VERSION 5.7 ;
  NOWIREEXTENSIONATPIN ON ;
  DIVIDERCHAR "/" ;
  BUSBITCHARS "[]" ;
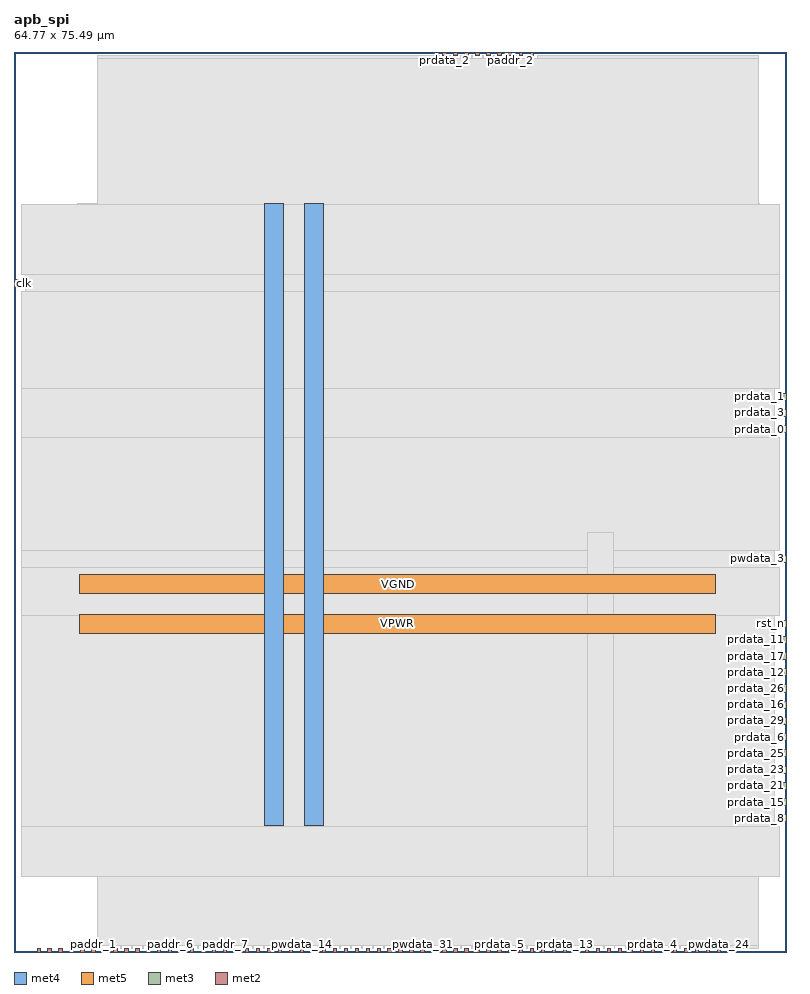
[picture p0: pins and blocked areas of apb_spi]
MACRO apb_spi
  CLASS BLOCK ;
  FOREIGN apb_spi ;
  ORIGIN 0.000 0.000 ;
  SIZE 64.770 BY 75.490 ;
  PIN VGND
    DIRECTION INOUT ;
    USE GROUND ;
    PORT
      LAYER met4 ;
        RECT 24.340 10.640 25.940 62.800 ;
    END
    PORT
      LAYER met5 ;
        RECT 5.520 30.030 58.880 31.630 ;
    END
  END VGND
  PIN VPWR
    DIRECTION INOUT ;
    USE POWER ;
    PORT
      LAYER met4 ;
        RECT 21.040 10.640 22.640 62.800 ;
    END
    PORT
      LAYER met5 ;
        RECT 5.520 26.730 58.880 28.330 ;
    END
  END VPWR
  PIN clk
    DIRECTION INPUT ;
    USE SIGNAL ;
    ANTENNAGATEAREA 1.286700 ;
    ANTENNADIFFAREA 0.434700 ;
    PORT
      LAYER met3 ;
        RECT 0.000 55.800 0.600 56.400 ;
    END
  END clk
  PIN paddr_0
    DIRECTION INPUT ;
    USE SIGNAL ;
    PORT
      LAYER met2 ;
        RECT 2.850 0.000 3.130 0.280 ;
    END
  END paddr_0
  PIN paddr_1
    DIRECTION INPUT ;
    USE SIGNAL ;
    PORT
      LAYER met2 ;
        RECT 6.530 0.000 6.810 0.280 ;
    END
  END paddr_1
  PIN paddr_10
    DIRECTION INPUT ;
    USE SIGNAL ;
    PORT
      LAYER met2 ;
        RECT 10.210 0.000 10.490 0.280 ;
    END
  END paddr_10
  PIN paddr_11
    DIRECTION INPUT ;
    USE SIGNAL ;
    PORT
      LAYER met2 ;
        RECT 8.370 0.000 8.650 0.280 ;
    END
  END paddr_11
  PIN paddr_2
    DIRECTION INPUT ;
    USE SIGNAL ;
    ANTENNAGATEAREA 0.647700 ;
    ANTENNADIFFAREA 0.434700 ;
    PORT
      LAYER met2 ;
        RECT 41.490 75.210 41.770 75.490 ;
    END
  END paddr_2
  PIN paddr_3
    DIRECTION INPUT ;
    USE SIGNAL ;
    ANTENNAGATEAREA 0.647700 ;
    ANTENNADIFFAREA 0.434700 ;
    PORT
      LAYER met2 ;
        RECT 40.570 75.210 40.850 75.490 ;
    END
  END paddr_3
  PIN paddr_4
    DIRECTION INPUT ;
    USE SIGNAL ;
    ANTENNAGATEAREA 0.647700 ;
    ANTENNADIFFAREA 0.434700 ;
    PORT
      LAYER met2 ;
        RECT 39.650 75.210 39.930 75.490 ;
    END
  END paddr_4
  PIN paddr_5
    DIRECTION INPUT ;
    USE SIGNAL ;
    PORT
      LAYER met2 ;
        RECT 5.610 0.000 5.890 0.280 ;
    END
  END paddr_5
  PIN paddr_6
    DIRECTION INPUT ;
    USE SIGNAL ;
    PORT
      LAYER met2 ;
        RECT 12.970 0.000 13.250 0.280 ;
    END
  END paddr_6
  PIN paddr_7
    DIRECTION INPUT ;
    USE SIGNAL ;
    PORT
      LAYER met2 ;
        RECT 17.570 0.000 17.850 0.280 ;
    END
  END paddr_7
  PIN paddr_8
    DIRECTION INPUT ;
    USE SIGNAL ;
    PORT
      LAYER met2 ;
        RECT 12.050 0.000 12.330 0.280 ;
    END
  END paddr_8
  PIN paddr_9
    DIRECTION INPUT ;
    USE SIGNAL ;
    PORT
      LAYER met2 ;
        RECT 9.290 0.000 9.570 0.280 ;
    END
  END paddr_9
  PIN penable
    DIRECTION INPUT ;
    USE SIGNAL ;
    ANTENNAGATEAREA 0.647700 ;
    ANTENNADIFFAREA 0.434700 ;
    PORT
      LAYER met2 ;
        RECT 38.730 75.210 39.010 75.490 ;
    END
  END penable
  PIN prdata_0
    DIRECTION OUTPUT ;
    USE SIGNAL ;
    ANTENNAGATEAREA 0.434700 ;
    ANTENNADIFFAREA 1.137600 ;
    PORT
      LAYER met3 ;
        RECT 64.170 43.560 64.770 44.160 ;
    END
  END prdata_0
  PIN prdata_1
    DIRECTION OUTPUT ;
    USE SIGNAL ;
    ANTENNAGATEAREA 0.434700 ;
    ANTENNADIFFAREA 1.137600 ;
    PORT
      LAYER met3 ;
        RECT 64.170 46.280 64.770 46.880 ;
    END
  END prdata_1
  PIN prdata_10
    DIRECTION OUTPUT ;
    USE SIGNAL ;
    ANTENNAGATEAREA 0.434700 ;
    ANTENNADIFFAREA 0.775300 ;
    PORT
      LAYER met2 ;
        RECT 35.050 0.000 35.330 0.280 ;
    END
  END prdata_10
  PIN prdata_11
    DIRECTION OUTPUT ;
    USE SIGNAL ;
    ANTENNAGATEAREA 0.434700 ;
    ANTENNADIFFAREA 0.775300 ;
    PORT
      LAYER met3 ;
        RECT 64.170 25.880 64.770 26.480 ;
    END
  END prdata_11
  PIN prdata_12
    DIRECTION OUTPUT ;
    USE SIGNAL ;
    ANTENNAGATEAREA 0.434700 ;
    ANTENNADIFFAREA 0.775300 ;
    PORT
      LAYER met3 ;
        RECT 64.170 23.160 64.770 23.760 ;
    END
  END prdata_12
  PIN prdata_13
    DIRECTION OUTPUT ;
    USE SIGNAL ;
    ANTENNAGATEAREA 0.434700 ;
    ANTENNADIFFAREA 0.775300 ;
    PORT
      LAYER met2 ;
        RECT 46.090 0.000 46.370 0.280 ;
    END
  END prdata_13
  PIN prdata_14
    DIRECTION OUTPUT ;
    USE SIGNAL ;
    ANTENNAGATEAREA 0.434700 ;
    ANTENNADIFFAREA 0.775300 ;
    PORT
      LAYER met2 ;
        RECT 52.530 0.000 52.810 0.280 ;
    END
  END prdata_14
  PIN prdata_15
    DIRECTION OUTPUT ;
    USE SIGNAL ;
    ANTENNAGATEAREA 0.434700 ;
    ANTENNADIFFAREA 0.775300 ;
    PORT
      LAYER met3 ;
        RECT 64.170 12.280 64.770 12.880 ;
    END
  END prdata_15
  PIN prdata_16
    DIRECTION OUTPUT ;
    USE SIGNAL ;
    ANTENNAGATEAREA 0.434700 ;
    ANTENNADIFFAREA 0.775300 ;
    PORT
      LAYER met3 ;
        RECT 64.170 20.440 64.770 21.040 ;
    END
  END prdata_16
  PIN prdata_17
    DIRECTION OUTPUT ;
    USE SIGNAL ;
    ANTENNAGATEAREA 0.434700 ;
    ANTENNADIFFAREA 0.775300 ;
    PORT
      LAYER met3 ;
        RECT 64.170 24.520 64.770 25.120 ;
    END
  END prdata_17
  PIN prdata_18
    DIRECTION OUTPUT ;
    USE SIGNAL ;
    ANTENNAGATEAREA 0.434700 ;
    ANTENNADIFFAREA 0.775300 ;
    PORT
      LAYER met2 ;
        RECT 51.610 0.000 51.890 0.280 ;
    END
  END prdata_18
  PIN prdata_19
    DIRECTION OUTPUT ;
    USE SIGNAL ;
    ANTENNAGATEAREA 0.434700 ;
    ANTENNADIFFAREA 0.775300 ;
    PORT
      LAYER met2 ;
        RECT 44.250 0.000 44.530 0.280 ;
    END
  END prdata_19
  PIN prdata_2
    DIRECTION OUTPUT ;
    USE SIGNAL ;
    ANTENNAGATEAREA 0.434700 ;
    ANTENNADIFFAREA 1.137600 ;
    PORT
      LAYER met2 ;
        RECT 35.970 75.210 36.250 75.490 ;
    END
  END prdata_2
  PIN prdata_20
    DIRECTION OUTPUT ;
    USE SIGNAL ;
    ANTENNAGATEAREA 0.434700 ;
    ANTENNADIFFAREA 0.775300 ;
    PORT
      LAYER met2 ;
        RECT 36.890 0.000 37.170 0.280 ;
    END
  END prdata_20
  PIN prdata_21
    DIRECTION OUTPUT ;
    USE SIGNAL ;
    ANTENNAGATEAREA 0.434700 ;
    ANTENNADIFFAREA 0.775300 ;
    PORT
      LAYER met3 ;
        RECT 64.170 13.640 64.770 14.240 ;
    END
  END prdata_21
  PIN prdata_22
    DIRECTION OUTPUT ;
    USE SIGNAL ;
    ANTENNAGATEAREA 0.434700 ;
    ANTENNADIFFAREA 0.775300 ;
    PORT
      LAYER met2 ;
        RECT 48.850 0.000 49.130 0.280 ;
    END
  END prdata_22
  PIN prdata_23
    DIRECTION OUTPUT ;
    USE SIGNAL ;
    ANTENNAGATEAREA 0.434700 ;
    ANTENNADIFFAREA 0.775300 ;
    PORT
      LAYER met3 ;
        RECT 64.170 15.000 64.770 15.600 ;
    END
  END prdata_23
  PIN prdata_24
    DIRECTION OUTPUT ;
    USE SIGNAL ;
    ANTENNAGATEAREA 0.434700 ;
    ANTENNADIFFAREA 0.775300 ;
    PORT
      LAYER met2 ;
        RECT 47.010 0.000 47.290 0.280 ;
    END
  END prdata_24
  PIN prdata_25
    DIRECTION OUTPUT ;
    USE SIGNAL ;
    ANTENNAGATEAREA 0.434700 ;
    ANTENNADIFFAREA 0.775300 ;
    PORT
      LAYER met3 ;
        RECT 64.170 16.360 64.770 16.960 ;
    END
  END prdata_25
  PIN prdata_26
    DIRECTION OUTPUT ;
    USE SIGNAL ;
    ANTENNAGATEAREA 0.434700 ;
    ANTENNADIFFAREA 0.775300 ;
    PORT
      LAYER met3 ;
        RECT 64.170 21.800 64.770 22.400 ;
    END
  END prdata_26
  PIN prdata_27
    DIRECTION OUTPUT ;
    USE SIGNAL ;
    ANTENNAGATEAREA 0.434700 ;
    ANTENNADIFFAREA 0.775300 ;
    PORT
      LAYER met2 ;
        RECT 37.810 0.000 38.090 0.280 ;
    END
  END prdata_27
  PIN prdata_28
    DIRECTION OUTPUT ;
    USE SIGNAL ;
    ANTENNAGATEAREA 0.434700 ;
    ANTENNADIFFAREA 0.775300 ;
    PORT
      LAYER met2 ;
        RECT 50.690 0.000 50.970 0.280 ;
    END
  END prdata_28
  PIN prdata_29
    DIRECTION OUTPUT ;
    USE SIGNAL ;
    ANTENNAGATEAREA 0.434700 ;
    ANTENNADIFFAREA 0.775300 ;
    PORT
      LAYER met3 ;
        RECT 64.170 19.080 64.770 19.680 ;
    END
  END prdata_29
  PIN prdata_3
    DIRECTION OUTPUT ;
    USE SIGNAL ;
    ANTENNAGATEAREA 0.434700 ;
    ANTENNADIFFAREA 1.137600 ;
    PORT
      LAYER met3 ;
        RECT 64.170 44.920 64.770 45.520 ;
    END
  END prdata_3
  PIN prdata_30
    DIRECTION OUTPUT ;
    USE SIGNAL ;
    ANTENNAGATEAREA 0.434700 ;
    ANTENNADIFFAREA 0.775300 ;
    PORT
      LAYER met2 ;
        RECT 49.770 0.000 50.050 0.280 ;
    END
  END prdata_30
  PIN prdata_31
    DIRECTION OUTPUT ;
    USE SIGNAL ;
    ANTENNAGATEAREA 0.434700 ;
    ANTENNADIFFAREA 0.775300 ;
    PORT
      LAYER met2 ;
        RECT 43.330 0.000 43.610 0.280 ;
    END
  END prdata_31
  PIN prdata_4
    DIRECTION OUTPUT ;
    USE SIGNAL ;
    ANTENNAGATEAREA 0.434700 ;
    ANTENNADIFFAREA 0.434700 ;
    PORT
      LAYER met2 ;
        RECT 53.450 0.000 53.730 0.280 ;
    END
  END prdata_4
  PIN prdata_5
    DIRECTION OUTPUT ;
    USE SIGNAL ;
    ANTENNAGATEAREA 0.434700 ;
    ANTENNADIFFAREA 0.775300 ;
    PORT
      LAYER met2 ;
        RECT 40.570 0.000 40.850 0.280 ;
    END
  END prdata_5
  PIN prdata_6
    DIRECTION OUTPUT ;
    USE SIGNAL ;
    ANTENNAGATEAREA 0.434700 ;
    ANTENNADIFFAREA 0.775300 ;
    PORT
      LAYER met3 ;
        RECT 64.170 17.720 64.770 18.320 ;
    END
  END prdata_6
  PIN prdata_7
    DIRECTION OUTPUT ;
    USE SIGNAL ;
    ANTENNAGATEAREA 0.434700 ;
    ANTENNADIFFAREA 0.775300 ;
    PORT
      LAYER met2 ;
        RECT 39.650 0.000 39.930 0.280 ;
    END
  END prdata_7
  PIN prdata_8
    DIRECTION OUTPUT ;
    USE SIGNAL ;
    ANTENNAGATEAREA 0.434700 ;
    ANTENNADIFFAREA 0.775300 ;
    PORT
      LAYER met3 ;
        RECT 64.170 10.920 64.770 11.520 ;
    END
  END prdata_8
  PIN prdata_9
    DIRECTION OUTPUT ;
    USE SIGNAL ;
    ANTENNAGATEAREA 0.434700 ;
    ANTENNADIFFAREA 0.775300 ;
    PORT
      LAYER met2 ;
        RECT 42.410 0.000 42.690 0.280 ;
    END
  END prdata_9
  PIN pready
    DIRECTION OUTPUT ;
    USE SIGNAL ;
    PORT
      LAYER met2 ;
        RECT 13.890 0.000 14.170 0.280 ;
    END
  END pready
  PIN psel
    DIRECTION INPUT ;
    USE SIGNAL ;
    ANTENNAGATEAREA 0.647700 ;
    ANTENNADIFFAREA 0.434700 ;
    PORT
      LAYER met2 ;
        RECT 36.890 75.210 37.170 75.490 ;
    END
  END psel
  PIN pslverr
    DIRECTION OUTPUT ;
    USE SIGNAL ;
    ANTENNAGATEAREA 0.434700 ;
    ANTENNADIFFAREA 0.775300 ;
    PORT
      LAYER met2 ;
        RECT 41.490 0.000 41.770 0.280 ;
    END
  END pslverr
  PIN pwdata_0
    DIRECTION INPUT ;
    USE SIGNAL ;
    ANTENNAGATEAREA 0.647700 ;
    ANTENNADIFFAREA 0.434700 ;
    PORT
      LAYER met2 ;
        RECT 30.450 0.000 30.730 0.280 ;
    END
  END pwdata_0
  PIN pwdata_1
    DIRECTION INPUT ;
    USE SIGNAL ;
    ANTENNAGATEAREA 0.647700 ;
    ANTENNADIFFAREA 0.434700 ;
    PORT
      LAYER met2 ;
        RECT 43.330 75.210 43.610 75.490 ;
    END
  END pwdata_1
  PIN pwdata_10
    DIRECTION INPUT ;
    USE SIGNAL ;
    PORT
      LAYER met2 ;
        RECT 14.810 0.000 15.090 0.280 ;
    END
  END pwdata_10
  PIN pwdata_11
    DIRECTION INPUT ;
    USE SIGNAL ;
    PORT
      LAYER met2 ;
        RECT 15.730 0.000 16.010 0.280 ;
    END
  END pwdata_11
  PIN pwdata_12
    DIRECTION INPUT ;
    USE SIGNAL ;
    PORT
      LAYER met2 ;
        RECT 19.410 0.000 19.690 0.280 ;
    END
  END pwdata_12
  PIN pwdata_13
    DIRECTION INPUT ;
    USE SIGNAL ;
    PORT
      LAYER met2 ;
        RECT 4.690 0.000 4.970 0.280 ;
    END
  END pwdata_13
  PIN pwdata_14
    DIRECTION INPUT ;
    USE SIGNAL ;
    PORT
      LAYER met2 ;
        RECT 24.010 0.000 24.290 0.280 ;
    END
  END pwdata_14
  PIN pwdata_15
    DIRECTION INPUT ;
    USE SIGNAL ;
    PORT
      LAYER met2 ;
        RECT 7.450 0.000 7.730 0.280 ;
    END
  END pwdata_15
  PIN pwdata_16
    DIRECTION INPUT ;
    USE SIGNAL ;
    PORT
      LAYER met2 ;
        RECT 33.210 0.000 33.490 0.280 ;
    END
  END pwdata_16
  PIN pwdata_17
    DIRECTION INPUT ;
    USE SIGNAL ;
    PORT
      LAYER met2 ;
        RECT 23.090 0.000 23.370 0.280 ;
    END
  END pwdata_17
  PIN pwdata_18
    DIRECTION INPUT ;
    USE SIGNAL ;
    PORT
      LAYER met2 ;
        RECT 18.490 0.000 18.770 0.280 ;
    END
  END pwdata_18
  PIN pwdata_19
    DIRECTION INPUT ;
    USE SIGNAL ;
    PORT
      LAYER met2 ;
        RECT 21.250 0.000 21.530 0.280 ;
    END
  END pwdata_19
  PIN pwdata_2
    DIRECTION INPUT ;
    USE SIGNAL ;
    ANTENNAGATEAREA 0.647700 ;
    ANTENNADIFFAREA 0.434700 ;
    PORT
      LAYER met2 ;
        RECT 42.410 75.210 42.690 75.490 ;
    END
  END pwdata_2
  PIN pwdata_20
    DIRECTION INPUT ;
    USE SIGNAL ;
    PORT
      LAYER met2 ;
        RECT 20.330 0.000 20.610 0.280 ;
    END
  END pwdata_20
  PIN pwdata_21
    DIRECTION INPUT ;
    USE SIGNAL ;
    PORT
      LAYER met2 ;
        RECT 26.770 0.000 27.050 0.280 ;
    END
  END pwdata_21
  PIN pwdata_22
    DIRECTION INPUT ;
    USE SIGNAL ;
    PORT
      LAYER met2 ;
        RECT 22.170 0.000 22.450 0.280 ;
    END
  END pwdata_22
  PIN pwdata_23
    DIRECTION INPUT ;
    USE SIGNAL ;
    PORT
      LAYER met2 ;
        RECT 24.930 0.000 25.210 0.280 ;
    END
  END pwdata_23
  PIN pwdata_24
    DIRECTION INPUT ;
    USE SIGNAL ;
    PORT
      LAYER met2 ;
        RECT 58.970 0.000 59.250 0.280 ;
    END
  END pwdata_24
  PIN pwdata_25
    DIRECTION INPUT ;
    USE SIGNAL ;
    PORT
      LAYER met2 ;
        RECT 27.690 0.000 27.970 0.280 ;
    END
  END pwdata_25
  PIN pwdata_26
    DIRECTION INPUT ;
    USE SIGNAL ;
    PORT
      LAYER met2 ;
        RECT 1.930 0.000 2.210 0.280 ;
    END
  END pwdata_26
  PIN pwdata_27
    DIRECTION INPUT ;
    USE SIGNAL ;
    PORT
      LAYER met2 ;
        RECT 32.290 0.000 32.570 0.280 ;
    END
  END pwdata_27
  PIN pwdata_28
    DIRECTION INPUT ;
    USE SIGNAL ;
    PORT
      LAYER met2 ;
        RECT 31.370 0.000 31.650 0.280 ;
    END
  END pwdata_28
  PIN pwdata_29
    DIRECTION INPUT ;
    USE SIGNAL ;
    PORT
      LAYER met2 ;
        RECT 55.290 0.000 55.570 0.280 ;
    END
  END pwdata_29
  PIN pwdata_3
    DIRECTION INPUT ;
    USE SIGNAL ;
    ANTENNAGATEAREA 0.647700 ;
    ANTENNADIFFAREA 0.434700 ;
    PORT
      LAYER met3 ;
        RECT 64.170 32.680 64.770 33.280 ;
    END
  END pwdata_3
  PIN pwdata_30
    DIRECTION INPUT ;
    USE SIGNAL ;
    PORT
      LAYER met2 ;
        RECT 29.530 0.000 29.810 0.280 ;
    END
  END pwdata_30
  PIN pwdata_31
    DIRECTION INPUT ;
    USE SIGNAL ;
    PORT
      LAYER met2 ;
        RECT 34.130 0.000 34.410 0.280 ;
    END
  END pwdata_31
  PIN pwdata_4
    DIRECTION INPUT ;
    USE SIGNAL ;
    ANTENNAGATEAREA 0.647700 ;
    ANTENNADIFFAREA 0.434700 ;
    PORT
      LAYER met2 ;
        RECT 38.730 0.000 39.010 0.280 ;
    END
  END pwdata_4
  PIN pwdata_5
    DIRECTION INPUT ;
    USE SIGNAL ;
    ANTENNAGATEAREA 0.647700 ;
    ANTENNADIFFAREA 0.434700 ;
    PORT
      LAYER met2 ;
        RECT 35.970 0.000 36.250 0.280 ;
    END
  END pwdata_5
  PIN pwdata_6
    DIRECTION INPUT ;
    USE SIGNAL ;
    ANTENNAGATEAREA 0.647700 ;
    ANTENNADIFFAREA 0.434700 ;
    PORT
      LAYER met2 ;
        RECT 28.610 0.000 28.890 0.280 ;
    END
  END pwdata_6
  PIN pwdata_7
    DIRECTION INPUT ;
    USE SIGNAL ;
    ANTENNAGATEAREA 0.647700 ;
    ANTENNADIFFAREA 0.434700 ;
    PORT
      LAYER met2 ;
        RECT 25.850 0.000 26.130 0.280 ;
    END
  END pwdata_7
  PIN pwdata_8
    DIRECTION INPUT ;
    USE SIGNAL ;
    PORT
      LAYER met2 ;
        RECT 58.050 0.000 58.330 0.280 ;
    END
  END pwdata_8
  PIN pwdata_9
    DIRECTION INPUT ;
    USE SIGNAL ;
    PORT
      LAYER met2 ;
        RECT 56.210 0.000 56.490 0.280 ;
    END
  END pwdata_9
  PIN pwrite
    DIRECTION INPUT ;
    USE SIGNAL ;
    ANTENNAGATEAREA 0.647700 ;
    ANTENNADIFFAREA 0.434700 ;
    PORT
      LAYER met2 ;
        RECT 37.810 75.210 38.090 75.490 ;
    END
  END pwrite
  PIN rst_n
    DIRECTION INPUT ;
    USE SIGNAL ;
    ANTENNAGATEAREA 0.647700 ;
    ANTENNADIFFAREA 0.434700 ;
    PORT
      LAYER met3 ;
        RECT 64.170 27.240 64.770 27.840 ;
    END
  END rst_n
  PIN spi_cs_n_0
    DIRECTION OUTPUT ;
    USE SIGNAL ;
    PORT
      LAYER met2 ;
        RECT 57.130 0.000 57.410 0.280 ;
    END
  END spi_cs_n_0
  PIN spi_cs_n_1
    DIRECTION OUTPUT ;
    USE SIGNAL ;
    PORT
      LAYER met2 ;
        RECT 3.770 0.000 4.050 0.280 ;
    END
  END spi_cs_n_1
  PIN spi_cs_n_2
    DIRECTION OUTPUT ;
    USE SIGNAL ;
    PORT
      LAYER met2 ;
        RECT 54.370 0.000 54.650 0.280 ;
    END
  END spi_cs_n_2
  PIN spi_cs_n_3
    DIRECTION OUTPUT ;
    USE SIGNAL ;
    PORT
      LAYER met2 ;
        RECT 16.650 0.000 16.930 0.280 ;
    END
  END spi_cs_n_3
  PIN spi_miso
    DIRECTION INPUT ;
    USE SIGNAL ;
    PORT
      LAYER met2 ;
        RECT 11.130 0.000 11.410 0.280 ;
    END
  END spi_miso
  PIN spi_mosi
    DIRECTION OUTPUT ;
    USE SIGNAL ;
    ANTENNAGATEAREA 0.434700 ;
    ANTENNADIFFAREA 0.775300 ;
    PORT
      LAYER met2 ;
        RECT 47.930 0.000 48.210 0.280 ;
    END
  END spi_mosi
  PIN spi_sclk
    DIRECTION OUTPUT ;
    USE SIGNAL ;
    ANTENNAGATEAREA 0.434700 ;
    ANTENNADIFFAREA 0.775300 ;
    PORT
      LAYER met2 ;
        RECT 45.170 0.000 45.450 0.280 ;
    END
  END spi_sclk
  OBS
      LAYER nwell ;
        RECT 5.330 10.795 59.070 62.750 ;
      LAYER li1 ;
        RECT 5.520 10.795 58.880 62.645 ;
      LAYER met1 ;
        RECT 5.520 6.500 62.490 62.800 ;
      LAYER met2 ;
        RECT 7.000 74.930 35.690 75.210 ;
        RECT 36.530 74.930 36.610 75.210 ;
        RECT 37.450 74.930 37.530 75.210 ;
        RECT 38.370 74.930 38.450 75.210 ;
        RECT 39.290 74.930 39.370 75.210 ;
        RECT 40.210 74.930 40.290 75.210 ;
        RECT 41.130 74.930 41.210 75.210 ;
        RECT 42.050 74.930 42.130 75.210 ;
        RECT 42.970 74.930 43.050 75.210 ;
        RECT 43.890 74.930 62.470 75.210 ;
        RECT 7.000 0.560 62.470 74.930 ;
        RECT 7.090 0.280 7.170 0.560 ;
        RECT 8.010 0.280 8.090 0.560 ;
        RECT 8.930 0.280 9.010 0.560 ;
        RECT 9.850 0.280 9.930 0.560 ;
        RECT 10.770 0.280 10.850 0.560 ;
        RECT 11.690 0.280 11.770 0.560 ;
        RECT 12.610 0.280 12.690 0.560 ;
        RECT 13.530 0.280 13.610 0.560 ;
        RECT 14.450 0.280 14.530 0.560 ;
        RECT 15.370 0.280 15.450 0.560 ;
        RECT 16.290 0.280 16.370 0.560 ;
        RECT 17.210 0.280 17.290 0.560 ;
        RECT 18.130 0.280 18.210 0.560 ;
        RECT 19.050 0.280 19.130 0.560 ;
        RECT 19.970 0.280 20.050 0.560 ;
        RECT 20.890 0.280 20.970 0.560 ;
        RECT 21.810 0.280 21.890 0.560 ;
        RECT 22.730 0.280 22.810 0.560 ;
        RECT 23.650 0.280 23.730 0.560 ;
        RECT 24.570 0.280 24.650 0.560 ;
        RECT 25.490 0.280 25.570 0.560 ;
        RECT 26.410 0.280 26.490 0.560 ;
        RECT 27.330 0.280 27.410 0.560 ;
        RECT 28.250 0.280 28.330 0.560 ;
        RECT 29.170 0.280 29.250 0.560 ;
        RECT 30.090 0.280 30.170 0.560 ;
        RECT 31.010 0.280 31.090 0.560 ;
        RECT 31.930 0.280 32.010 0.560 ;
        RECT 32.850 0.280 32.930 0.560 ;
        RECT 33.770 0.280 33.850 0.560 ;
        RECT 34.690 0.280 34.770 0.560 ;
        RECT 35.610 0.280 35.690 0.560 ;
        RECT 36.530 0.280 36.610 0.560 ;
        RECT 37.450 0.280 37.530 0.560 ;
        RECT 38.370 0.280 38.450 0.560 ;
        RECT 39.290 0.280 39.370 0.560 ;
        RECT 40.210 0.280 40.290 0.560 ;
        RECT 41.130 0.280 41.210 0.560 ;
        RECT 42.050 0.280 42.130 0.560 ;
        RECT 42.970 0.280 43.050 0.560 ;
        RECT 43.890 0.280 43.970 0.560 ;
        RECT 44.810 0.280 44.890 0.560 ;
        RECT 45.730 0.280 45.810 0.560 ;
        RECT 46.650 0.280 46.730 0.560 ;
        RECT 47.570 0.280 47.650 0.560 ;
        RECT 48.490 0.280 48.570 0.560 ;
        RECT 49.410 0.280 49.490 0.560 ;
        RECT 50.330 0.280 50.410 0.560 ;
        RECT 51.250 0.280 51.330 0.560 ;
        RECT 52.170 0.280 52.250 0.560 ;
        RECT 53.090 0.280 53.170 0.560 ;
        RECT 54.010 0.280 54.090 0.560 ;
        RECT 54.930 0.280 55.010 0.560 ;
        RECT 55.850 0.280 55.930 0.560 ;
        RECT 56.770 0.280 56.850 0.560 ;
        RECT 57.690 0.280 57.770 0.560 ;
        RECT 58.610 0.280 58.690 0.560 ;
        RECT 59.530 0.280 62.470 0.560 ;
      LAYER met3 ;
        RECT 0.600 56.800 64.170 62.725 ;
        RECT 1.000 55.400 64.170 56.800 ;
        RECT 0.600 47.280 64.170 55.400 ;
        RECT 0.600 43.160 63.770 47.280 ;
        RECT 0.600 33.680 64.170 43.160 ;
        RECT 0.600 32.280 63.770 33.680 ;
        RECT 0.600 28.240 64.170 32.280 ;
        RECT 0.600 10.520 63.770 28.240 ;
        RECT 0.600 6.295 64.170 10.520 ;
      LAYER met4 ;
        RECT 48.135 6.295 50.305 35.185 ;
  END
END apb_spi
END LIBRARY

